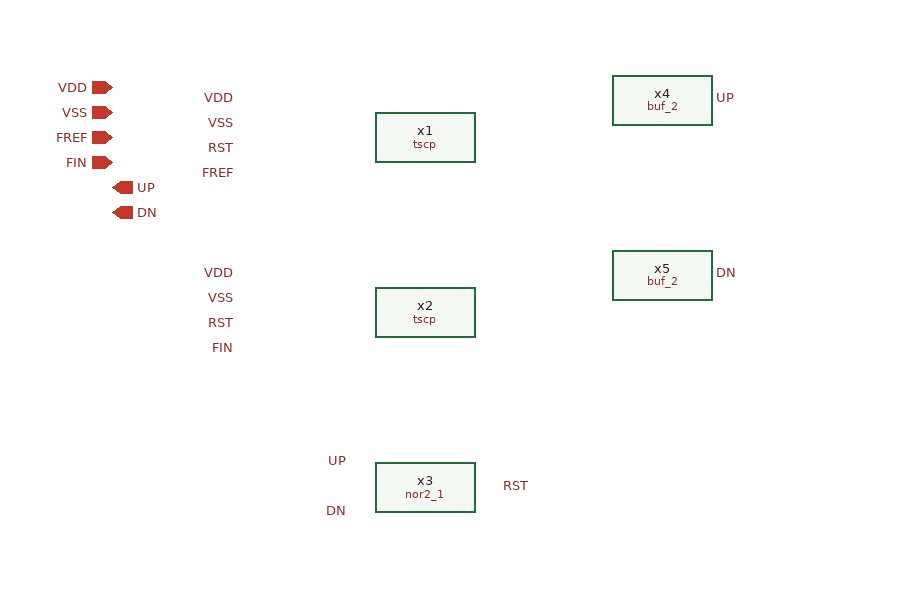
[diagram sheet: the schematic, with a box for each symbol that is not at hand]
v {xschem version=3.4.6 file_version=1.2}
G {}
K {}
V {}
S {}
E {}
C {tscp.sym} 410 -360 0 0 {name=x1}
C {tscp.sym} 410 -220 0 0 {name=x2}
C {devices/lab_wire.sym} 260 -390 0 0 {name=p5 sig_type=std_logic lab=VDD}
C {devices/lab_wire.sym} 260 -250 0 0 {name=p1 sig_type=std_logic lab=VDD}
C {devices/lab_wire.sym} 260 -370 0 0 {name=p2 sig_type=std_logic lab=VSS}
C {devices/lab_wire.sym} 260 -230 0 0 {name=p3 sig_type=std_logic lab=VSS}
C {devices/lab_wire.sym} 260 -350 0 0 {name=p4 sig_type=std_logic lab=RST}
C {devices/lab_wire.sym} 260 -210 0 0 {name=p6 sig_type=std_logic lab=RST}
C {devices/lab_wire.sym} 260 -330 0 0 {name=p7 sig_type=std_logic lab=FREF}
C {devices/lab_wire.sym} 260 -190 0 0 {name=p8 sig_type=std_logic lab=FIN}
C {devices/lab_wire.sym} 640 -390 0 1 {name=p9 sig_type=std_logic lab=UP}
C {devices/lab_wire.sym} 640 -250 0 1 {name=p10 sig_type=std_logic lab=DN}
C {sky130_stdcells/nor2_1.sym} 410 -80 0 0 {name=x3 VGND=VSS VNB=VSS VPB=VDD VPWR=VDD prefix=sky130_fd_sc_hd__ }
C {devices/lab_wire.sym} 350 -100 0 0 {name=p11 sig_type=std_logic lab=UP}
C {devices/lab_wire.sym} 350 -60 0 0 {name=p12 sig_type=std_logic lab=DN}
C {devices/lab_wire.sym} 470 -80 0 1 {name=p13 sig_type=std_logic lab=RST}
C {devices/ipin.sym} 160 -400 0 0 {name=p14 sig_type=std_logic lab=VDD}
C {devices/ipin.sym} 160 -380 0 0 {name=p15 sig_type=std_logic lab=VSS}
C {devices/ipin.sym} 160 -360 0 0 {name=p16 sig_type=std_logic lab=FREF}
C {devices/ipin.sym} 160 -340 0 0 {name=p17 sig_type=std_logic lab=FIN}
C {devices/opin.sym} 160 -320 0 0 {name=p18 sig_type=std_logic lab=UP}
C {devices/opin.sym} 160 -300 0 0 {name=p19 sig_type=std_logic lab=DN}
C {sky130_stdcells/buf_2.sym} 600 -390 0 0 {name=x4 VGND=VSS VNB=VSS VPB=VDD VPWR=VDD prefix=sky130_fd_sc_hd__ }
C {sky130_stdcells/buf_2.sym} 600 -250 0 0 {name=x5 VGND=VSS VNB=VSS VPB=VDD VPWR=VDD prefix=sky130_fd_sc_hd__ }
